VERSION 5.7 ;
BUSBITCHARS "[]" ;
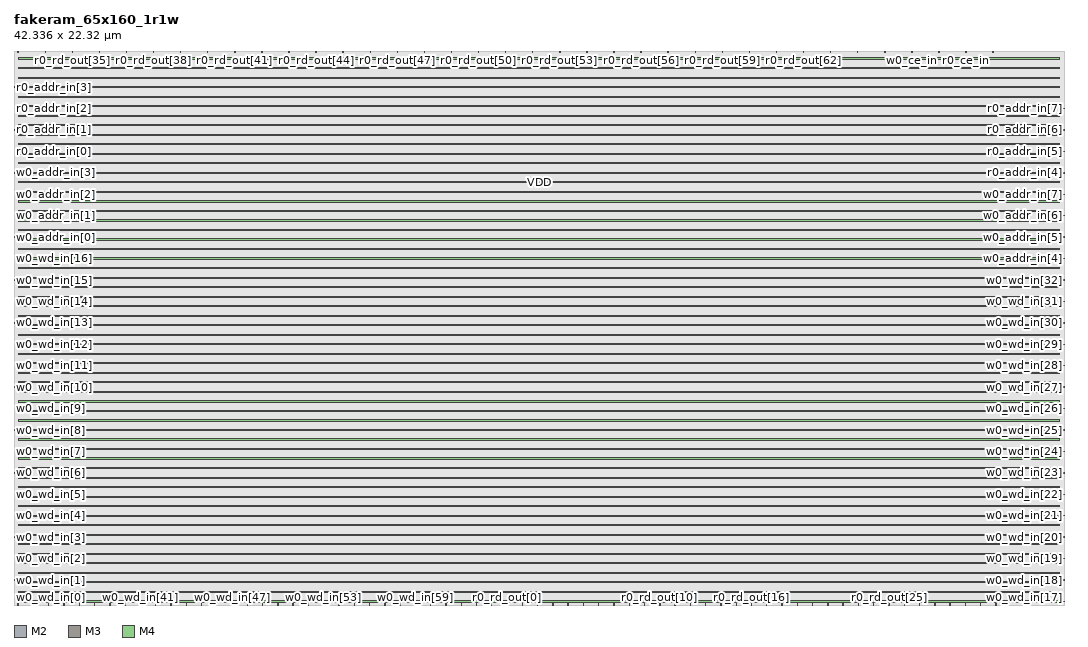
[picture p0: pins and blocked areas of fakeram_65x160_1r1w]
MACRO fakeram_65x160_1r1w
  FOREIGN fakeram_65x160_1r1w 0 0 ;
  SYMMETRY X Y R90 ;
  SIZE 42.336 BY 22.320 ;
  CLASS BLOCK ;
  PIN w0_wd_in[0]
    DIRECTION INPUT ;
    USE SIGNAL ;
    SHAPE ABUTMENT ;
    PORT
      LAYER M2 ;
      RECT 0.000 0.138 0.036 0.150 ;
    END
  END w0_wd_in[0]
  PIN w0_wd_in[1]
    DIRECTION INPUT ;
    USE SIGNAL ;
    SHAPE ABUTMENT ;
    PORT
      LAYER M2 ;
      RECT 0.000 1.002 0.036 1.014 ;
    END
  END w0_wd_in[1]
  PIN w0_wd_in[2]
    DIRECTION INPUT ;
    USE SIGNAL ;
    SHAPE ABUTMENT ;
    PORT
      LAYER M2 ;
      RECT 0.000 1.866 0.036 1.878 ;
    END
  END w0_wd_in[2]
  PIN w0_wd_in[3]
    DIRECTION INPUT ;
    USE SIGNAL ;
    SHAPE ABUTMENT ;
    PORT
      LAYER M2 ;
      RECT 0.000 2.730 0.036 2.742 ;
    END
  END w0_wd_in[3]
  PIN w0_wd_in[4]
    DIRECTION INPUT ;
    USE SIGNAL ;
    SHAPE ABUTMENT ;
    PORT
      LAYER M2 ;
      RECT 0.000 3.594 0.036 3.606 ;
    END
  END w0_wd_in[4]
  PIN w0_wd_in[5]
    DIRECTION INPUT ;
    USE SIGNAL ;
    SHAPE ABUTMENT ;
    PORT
      LAYER M2 ;
      RECT 0.000 4.458 0.036 4.470 ;
    END
  END w0_wd_in[5]
  PIN w0_wd_in[6]
    DIRECTION INPUT ;
    USE SIGNAL ;
    SHAPE ABUTMENT ;
    PORT
      LAYER M2 ;
      RECT 0.000 5.322 0.036 5.334 ;
    END
  END w0_wd_in[6]
  PIN w0_wd_in[7]
    DIRECTION INPUT ;
    USE SIGNAL ;
    SHAPE ABUTMENT ;
    PORT
      LAYER M2 ;
      RECT 0.000 6.186 0.036 6.198 ;
    END
  END w0_wd_in[7]
  PIN w0_wd_in[8]
    DIRECTION INPUT ;
    USE SIGNAL ;
    SHAPE ABUTMENT ;
    PORT
      LAYER M2 ;
      RECT 0.000 7.050 0.036 7.062 ;
    END
  END w0_wd_in[8]
  PIN w0_wd_in[9]
    DIRECTION INPUT ;
    USE SIGNAL ;
    SHAPE ABUTMENT ;
    PORT
      LAYER M2 ;
      RECT 0.000 7.914 0.036 7.926 ;
    END
  END w0_wd_in[9]
  PIN w0_wd_in[10]
    DIRECTION INPUT ;
    USE SIGNAL ;
    SHAPE ABUTMENT ;
    PORT
      LAYER M2 ;
      RECT 0.000 8.778 0.036 8.790 ;
    END
  END w0_wd_in[10]
  PIN w0_wd_in[11]
    DIRECTION INPUT ;
    USE SIGNAL ;
    SHAPE ABUTMENT ;
    PORT
      LAYER M2 ;
      RECT 0.000 9.642 0.036 9.654 ;
    END
  END w0_wd_in[11]
  PIN w0_wd_in[12]
    DIRECTION INPUT ;
    USE SIGNAL ;
    SHAPE ABUTMENT ;
    PORT
      LAYER M2 ;
      RECT 0.000 10.506 0.036 10.518 ;
    END
  END w0_wd_in[12]
  PIN w0_wd_in[13]
    DIRECTION INPUT ;
    USE SIGNAL ;
    SHAPE ABUTMENT ;
    PORT
      LAYER M2 ;
      RECT 0.000 11.370 0.036 11.382 ;
    END
  END w0_wd_in[13]
  PIN w0_wd_in[14]
    DIRECTION INPUT ;
    USE SIGNAL ;
    SHAPE ABUTMENT ;
    PORT
      LAYER M2 ;
      RECT 0.000 12.234 0.036 12.246 ;
    END
  END w0_wd_in[14]
  PIN w0_wd_in[15]
    DIRECTION INPUT ;
    USE SIGNAL ;
    SHAPE ABUTMENT ;
    PORT
      LAYER M2 ;
      RECT 0.000 13.098 0.036 13.110 ;
    END
  END w0_wd_in[15]
  PIN w0_wd_in[16]
    DIRECTION INPUT ;
    USE SIGNAL ;
    SHAPE ABUTMENT ;
    PORT
      LAYER M2 ;
      RECT 0.000 13.962 0.036 13.974 ;
    END
  END w0_wd_in[16]
  PIN w0_wd_in[17]
    DIRECTION INPUT ;
    USE SIGNAL ;
    SHAPE ABUTMENT ;
    PORT
      LAYER M2 ;
      RECT 42.300 0.138 42.336 0.150 ;
    END
  END w0_wd_in[17]
  PIN w0_wd_in[18]
    DIRECTION INPUT ;
    USE SIGNAL ;
    SHAPE ABUTMENT ;
    PORT
      LAYER M2 ;
      RECT 42.300 1.002 42.336 1.014 ;
    END
  END w0_wd_in[18]
  PIN w0_wd_in[19]
    DIRECTION INPUT ;
    USE SIGNAL ;
    SHAPE ABUTMENT ;
    PORT
      LAYER M2 ;
      RECT 42.300 1.866 42.336 1.878 ;
    END
  END w0_wd_in[19]
  PIN w0_wd_in[20]
    DIRECTION INPUT ;
    USE SIGNAL ;
    SHAPE ABUTMENT ;
    PORT
      LAYER M2 ;
      RECT 42.300 2.730 42.336 2.742 ;
    END
  END w0_wd_in[20]
  PIN w0_wd_in[21]
    DIRECTION INPUT ;
    USE SIGNAL ;
    SHAPE ABUTMENT ;
    PORT
      LAYER M2 ;
      RECT 42.300 3.594 42.336 3.606 ;
    END
  END w0_wd_in[21]
  PIN w0_wd_in[22]
    DIRECTION INPUT ;
    USE SIGNAL ;
    SHAPE ABUTMENT ;
    PORT
      LAYER M2 ;
      RECT 42.300 4.458 42.336 4.470 ;
    END
  END w0_wd_in[22]
  PIN w0_wd_in[23]
    DIRECTION INPUT ;
    USE SIGNAL ;
    SHAPE ABUTMENT ;
    PORT
      LAYER M2 ;
      RECT 42.300 5.322 42.336 5.334 ;
    END
  END w0_wd_in[23]
  PIN w0_wd_in[24]
    DIRECTION INPUT ;
    USE SIGNAL ;
    SHAPE ABUTMENT ;
    PORT
      LAYER M2 ;
      RECT 42.300 6.186 42.336 6.198 ;
    END
  END w0_wd_in[24]
  PIN w0_wd_in[25]
    DIRECTION INPUT ;
    USE SIGNAL ;
    SHAPE ABUTMENT ;
    PORT
      LAYER M2 ;
      RECT 42.300 7.050 42.336 7.062 ;
    END
  END w0_wd_in[25]
  PIN w0_wd_in[26]
    DIRECTION INPUT ;
    USE SIGNAL ;
    SHAPE ABUTMENT ;
    PORT
      LAYER M2 ;
      RECT 42.300 7.914 42.336 7.926 ;
    END
  END w0_wd_in[26]
  PIN w0_wd_in[27]
    DIRECTION INPUT ;
    USE SIGNAL ;
    SHAPE ABUTMENT ;
    PORT
      LAYER M2 ;
      RECT 42.300 8.778 42.336 8.790 ;
    END
  END w0_wd_in[27]
  PIN w0_wd_in[28]
    DIRECTION INPUT ;
    USE SIGNAL ;
    SHAPE ABUTMENT ;
    PORT
      LAYER M2 ;
      RECT 42.300 9.642 42.336 9.654 ;
    END
  END w0_wd_in[28]
  PIN w0_wd_in[29]
    DIRECTION INPUT ;
    USE SIGNAL ;
    SHAPE ABUTMENT ;
    PORT
      LAYER M2 ;
      RECT 42.300 10.506 42.336 10.518 ;
    END
  END w0_wd_in[29]
  PIN w0_wd_in[30]
    DIRECTION INPUT ;
    USE SIGNAL ;
    SHAPE ABUTMENT ;
    PORT
      LAYER M2 ;
      RECT 42.300 11.370 42.336 11.382 ;
    END
  END w0_wd_in[30]
  PIN w0_wd_in[31]
    DIRECTION INPUT ;
    USE SIGNAL ;
    SHAPE ABUTMENT ;
    PORT
      LAYER M2 ;
      RECT 42.300 12.234 42.336 12.246 ;
    END
  END w0_wd_in[31]
  PIN w0_wd_in[32]
    DIRECTION INPUT ;
    USE SIGNAL ;
    SHAPE ABUTMENT ;
    PORT
      LAYER M2 ;
      RECT 42.300 13.098 42.336 13.110 ;
    END
  END w0_wd_in[32]
  PIN w0_wd_in[33]
    DIRECTION INPUT ;
    USE SIGNAL ;
    SHAPE ABUTMENT ;
    PORT
      LAYER M3 ;
      RECT 0.161 0.000 0.175 0.042 ;
    END
  END w0_wd_in[33]
  PIN w0_wd_in[34]
    DIRECTION INPUT ;
    USE SIGNAL ;
    SHAPE ABUTMENT ;
    PORT
      LAYER M3 ;
      RECT 0.777 0.000 0.791 0.042 ;
    END
  END w0_wd_in[34]
  PIN w0_wd_in[35]
    DIRECTION INPUT ;
    USE SIGNAL ;
    SHAPE ABUTMENT ;
    PORT
      LAYER M3 ;
      RECT 1.393 0.000 1.407 0.042 ;
    END
  END w0_wd_in[35]
  PIN w0_wd_in[36]
    DIRECTION INPUT ;
    USE SIGNAL ;
    SHAPE ABUTMENT ;
    PORT
      LAYER M3 ;
      RECT 2.009 0.000 2.023 0.042 ;
    END
  END w0_wd_in[36]
  PIN w0_wd_in[37]
    DIRECTION INPUT ;
    USE SIGNAL ;
    SHAPE ABUTMENT ;
    PORT
      LAYER M3 ;
      RECT 2.625 0.000 2.639 0.042 ;
    END
  END w0_wd_in[37]
  PIN w0_wd_in[38]
    DIRECTION INPUT ;
    USE SIGNAL ;
    SHAPE ABUTMENT ;
    PORT
      LAYER M3 ;
      RECT 3.241 0.000 3.255 0.042 ;
    END
  END w0_wd_in[38]
  PIN w0_wd_in[39]
    DIRECTION INPUT ;
    USE SIGNAL ;
    SHAPE ABUTMENT ;
    PORT
      LAYER M3 ;
      RECT 3.857 0.000 3.871 0.042 ;
    END
  END w0_wd_in[39]
  PIN w0_wd_in[40]
    DIRECTION INPUT ;
    USE SIGNAL ;
    SHAPE ABUTMENT ;
    PORT
      LAYER M3 ;
      RECT 4.473 0.000 4.487 0.042 ;
    END
  END w0_wd_in[40]
  PIN w0_wd_in[41]
    DIRECTION INPUT ;
    USE SIGNAL ;
    SHAPE ABUTMENT ;
    PORT
      LAYER M3 ;
      RECT 5.089 0.000 5.103 0.042 ;
    END
  END w0_wd_in[41]
  PIN w0_wd_in[42]
    DIRECTION INPUT ;
    USE SIGNAL ;
    SHAPE ABUTMENT ;
    PORT
      LAYER M3 ;
      RECT 5.705 0.000 5.719 0.042 ;
    END
  END w0_wd_in[42]
  PIN w0_wd_in[43]
    DIRECTION INPUT ;
    USE SIGNAL ;
    SHAPE ABUTMENT ;
    PORT
      LAYER M3 ;
      RECT 6.321 0.000 6.335 0.042 ;
    END
  END w0_wd_in[43]
  PIN w0_wd_in[44]
    DIRECTION INPUT ;
    USE SIGNAL ;
    SHAPE ABUTMENT ;
    PORT
      LAYER M3 ;
      RECT 6.937 0.000 6.951 0.042 ;
    END
  END w0_wd_in[44]
  PIN w0_wd_in[45]
    DIRECTION INPUT ;
    USE SIGNAL ;
    SHAPE ABUTMENT ;
    PORT
      LAYER M3 ;
      RECT 7.553 0.000 7.567 0.042 ;
    END
  END w0_wd_in[45]
  PIN w0_wd_in[46]
    DIRECTION INPUT ;
    USE SIGNAL ;
    SHAPE ABUTMENT ;
    PORT
      LAYER M3 ;
      RECT 8.169 0.000 8.183 0.042 ;
    END
  END w0_wd_in[46]
  PIN w0_wd_in[47]
    DIRECTION INPUT ;
    USE SIGNAL ;
    SHAPE ABUTMENT ;
    PORT
      LAYER M3 ;
      RECT 8.785 0.000 8.799 0.042 ;
    END
  END w0_wd_in[47]
  PIN w0_wd_in[48]
    DIRECTION INPUT ;
    USE SIGNAL ;
    SHAPE ABUTMENT ;
    PORT
      LAYER M3 ;
      RECT 9.401 0.000 9.415 0.042 ;
    END
  END w0_wd_in[48]
  PIN w0_wd_in[49]
    DIRECTION INPUT ;
    USE SIGNAL ;
    SHAPE ABUTMENT ;
    PORT
      LAYER M3 ;
      RECT 10.017 0.000 10.031 0.042 ;
    END
  END w0_wd_in[49]
  PIN w0_wd_in[50]
    DIRECTION INPUT ;
    USE SIGNAL ;
    SHAPE ABUTMENT ;
    PORT
      LAYER M3 ;
      RECT 10.633 0.000 10.647 0.042 ;
    END
  END w0_wd_in[50]
  PIN w0_wd_in[51]
    DIRECTION INPUT ;
    USE SIGNAL ;
    SHAPE ABUTMENT ;
    PORT
      LAYER M3 ;
      RECT 11.249 0.000 11.263 0.042 ;
    END
  END w0_wd_in[51]
  PIN w0_wd_in[52]
    DIRECTION INPUT ;
    USE SIGNAL ;
    SHAPE ABUTMENT ;
    PORT
      LAYER M3 ;
      RECT 11.865 0.000 11.879 0.042 ;
    END
  END w0_wd_in[52]
  PIN w0_wd_in[53]
    DIRECTION INPUT ;
    USE SIGNAL ;
    SHAPE ABUTMENT ;
    PORT
      LAYER M3 ;
      RECT 12.481 0.000 12.495 0.042 ;
    END
  END w0_wd_in[53]
  PIN w0_wd_in[54]
    DIRECTION INPUT ;
    USE SIGNAL ;
    SHAPE ABUTMENT ;
    PORT
      LAYER M3 ;
      RECT 13.097 0.000 13.111 0.042 ;
    END
  END w0_wd_in[54]
  PIN w0_wd_in[55]
    DIRECTION INPUT ;
    USE SIGNAL ;
    SHAPE ABUTMENT ;
    PORT
      LAYER M3 ;
      RECT 13.713 0.000 13.727 0.042 ;
    END
  END w0_wd_in[55]
  PIN w0_wd_in[56]
    DIRECTION INPUT ;
    USE SIGNAL ;
    SHAPE ABUTMENT ;
    PORT
      LAYER M3 ;
      RECT 14.329 0.000 14.343 0.042 ;
    END
  END w0_wd_in[56]
  PIN w0_wd_in[57]
    DIRECTION INPUT ;
    USE SIGNAL ;
    SHAPE ABUTMENT ;
    PORT
      LAYER M3 ;
      RECT 14.945 0.000 14.959 0.042 ;
    END
  END w0_wd_in[57]
  PIN w0_wd_in[58]
    DIRECTION INPUT ;
    USE SIGNAL ;
    SHAPE ABUTMENT ;
    PORT
      LAYER M3 ;
      RECT 15.561 0.000 15.575 0.042 ;
    END
  END w0_wd_in[58]
  PIN w0_wd_in[59]
    DIRECTION INPUT ;
    USE SIGNAL ;
    SHAPE ABUTMENT ;
    PORT
      LAYER M3 ;
      RECT 16.177 0.000 16.191 0.042 ;
    END
  END w0_wd_in[59]
  PIN w0_wd_in[60]
    DIRECTION INPUT ;
    USE SIGNAL ;
    SHAPE ABUTMENT ;
    PORT
      LAYER M3 ;
      RECT 16.793 0.000 16.807 0.042 ;
    END
  END w0_wd_in[60]
  PIN w0_wd_in[61]
    DIRECTION INPUT ;
    USE SIGNAL ;
    SHAPE ABUTMENT ;
    PORT
      LAYER M3 ;
      RECT 17.409 0.000 17.423 0.042 ;
    END
  END w0_wd_in[61]
  PIN w0_wd_in[62]
    DIRECTION INPUT ;
    USE SIGNAL ;
    SHAPE ABUTMENT ;
    PORT
      LAYER M3 ;
      RECT 18.025 0.000 18.039 0.042 ;
    END
  END w0_wd_in[62]
  PIN w0_wd_in[63]
    DIRECTION INPUT ;
    USE SIGNAL ;
    SHAPE ABUTMENT ;
    PORT
      LAYER M3 ;
      RECT 18.641 0.000 18.655 0.042 ;
    END
  END w0_wd_in[63]
  PIN w0_wd_in[64]
    DIRECTION INPUT ;
    USE SIGNAL ;
    SHAPE ABUTMENT ;
    PORT
      LAYER M3 ;
      RECT 19.257 0.000 19.271 0.042 ;
    END
  END w0_wd_in[64]
  PIN r0_rd_out[0]
    DIRECTION OUTPUT ;
    USE SIGNAL ;
    SHAPE ABUTMENT ;
    PORT
      LAYER M3 ;
      RECT 19.873 0.000 19.887 0.042 ;
    END
  END r0_rd_out[0]
  PIN r0_rd_out[1]
    DIRECTION OUTPUT ;
    USE SIGNAL ;
    SHAPE ABUTMENT ;
    PORT
      LAYER M3 ;
      RECT 20.489 0.000 20.503 0.042 ;
    END
  END r0_rd_out[1]
  PIN r0_rd_out[2]
    DIRECTION OUTPUT ;
    USE SIGNAL ;
    SHAPE ABUTMENT ;
    PORT
      LAYER M3 ;
      RECT 21.105 0.000 21.119 0.042 ;
    END
  END r0_rd_out[2]
  PIN r0_rd_out[3]
    DIRECTION OUTPUT ;
    USE SIGNAL ;
    SHAPE ABUTMENT ;
    PORT
      LAYER M3 ;
      RECT 21.721 0.000 21.735 0.042 ;
    END
  END r0_rd_out[3]
  PIN r0_rd_out[4]
    DIRECTION OUTPUT ;
    USE SIGNAL ;
    SHAPE ABUTMENT ;
    PORT
      LAYER M3 ;
      RECT 22.337 0.000 22.351 0.042 ;
    END
  END r0_rd_out[4]
  PIN r0_rd_out[5]
    DIRECTION OUTPUT ;
    USE SIGNAL ;
    SHAPE ABUTMENT ;
    PORT
      LAYER M3 ;
      RECT 22.953 0.000 22.967 0.042 ;
    END
  END r0_rd_out[5]
  PIN r0_rd_out[6]
    DIRECTION OUTPUT ;
    USE SIGNAL ;
    SHAPE ABUTMENT ;
    PORT
      LAYER M3 ;
      RECT 23.569 0.000 23.583 0.042 ;
    END
  END r0_rd_out[6]
  PIN r0_rd_out[7]
    DIRECTION OUTPUT ;
    USE SIGNAL ;
    SHAPE ABUTMENT ;
    PORT
      LAYER M3 ;
      RECT 24.185 0.000 24.199 0.042 ;
    END
  END r0_rd_out[7]
  PIN r0_rd_out[8]
    DIRECTION OUTPUT ;
    USE SIGNAL ;
    SHAPE ABUTMENT ;
    PORT
      LAYER M3 ;
      RECT 24.801 0.000 24.815 0.042 ;
    END
  END r0_rd_out[8]
  PIN r0_rd_out[9]
    DIRECTION OUTPUT ;
    USE SIGNAL ;
    SHAPE ABUTMENT ;
    PORT
      LAYER M3 ;
      RECT 25.417 0.000 25.431 0.042 ;
    END
  END r0_rd_out[9]
  PIN r0_rd_out[10]
    DIRECTION OUTPUT ;
    USE SIGNAL ;
    SHAPE ABUTMENT ;
    PORT
      LAYER M3 ;
      RECT 26.033 0.000 26.047 0.042 ;
    END
  END r0_rd_out[10]
  PIN r0_rd_out[11]
    DIRECTION OUTPUT ;
    USE SIGNAL ;
    SHAPE ABUTMENT ;
    PORT
      LAYER M3 ;
      RECT 26.649 0.000 26.663 0.042 ;
    END
  END r0_rd_out[11]
  PIN r0_rd_out[12]
    DIRECTION OUTPUT ;
    USE SIGNAL ;
    SHAPE ABUTMENT ;
    PORT
      LAYER M3 ;
      RECT 27.265 0.000 27.279 0.042 ;
    END
  END r0_rd_out[12]
  PIN r0_rd_out[13]
    DIRECTION OUTPUT ;
    USE SIGNAL ;
    SHAPE ABUTMENT ;
    PORT
      LAYER M3 ;
      RECT 27.881 0.000 27.895 0.042 ;
    END
  END r0_rd_out[13]
  PIN r0_rd_out[14]
    DIRECTION OUTPUT ;
    USE SIGNAL ;
    SHAPE ABUTMENT ;
    PORT
      LAYER M3 ;
      RECT 28.497 0.000 28.511 0.042 ;
    END
  END r0_rd_out[14]
  PIN r0_rd_out[15]
    DIRECTION OUTPUT ;
    USE SIGNAL ;
    SHAPE ABUTMENT ;
    PORT
      LAYER M3 ;
      RECT 29.113 0.000 29.127 0.042 ;
    END
  END r0_rd_out[15]
  PIN r0_rd_out[16]
    DIRECTION OUTPUT ;
    USE SIGNAL ;
    SHAPE ABUTMENT ;
    PORT
      LAYER M3 ;
      RECT 29.729 0.000 29.743 0.042 ;
    END
  END r0_rd_out[16]
  PIN r0_rd_out[17]
    DIRECTION OUTPUT ;
    USE SIGNAL ;
    SHAPE ABUTMENT ;
    PORT
      LAYER M3 ;
      RECT 30.345 0.000 30.359 0.042 ;
    END
  END r0_rd_out[17]
  PIN r0_rd_out[18]
    DIRECTION OUTPUT ;
    USE SIGNAL ;
    SHAPE ABUTMENT ;
    PORT
      LAYER M3 ;
      RECT 30.961 0.000 30.975 0.042 ;
    END
  END r0_rd_out[18]
  PIN r0_rd_out[19]
    DIRECTION OUTPUT ;
    USE SIGNAL ;
    SHAPE ABUTMENT ;
    PORT
      LAYER M3 ;
      RECT 31.577 0.000 31.591 0.042 ;
    END
  END r0_rd_out[19]
  PIN r0_rd_out[20]
    DIRECTION OUTPUT ;
    USE SIGNAL ;
    SHAPE ABUTMENT ;
    PORT
      LAYER M3 ;
      RECT 32.193 0.000 32.207 0.042 ;
    END
  END r0_rd_out[20]
  PIN r0_rd_out[21]
    DIRECTION OUTPUT ;
    USE SIGNAL ;
    SHAPE ABUTMENT ;
    PORT
      LAYER M3 ;
      RECT 32.809 0.000 32.823 0.042 ;
    END
  END r0_rd_out[21]
  PIN r0_rd_out[22]
    DIRECTION OUTPUT ;
    USE SIGNAL ;
    SHAPE ABUTMENT ;
    PORT
      LAYER M3 ;
      RECT 33.425 0.000 33.439 0.042 ;
    END
  END r0_rd_out[22]
  PIN r0_rd_out[23]
    DIRECTION OUTPUT ;
    USE SIGNAL ;
    SHAPE ABUTMENT ;
    PORT
      LAYER M3 ;
      RECT 34.041 0.000 34.055 0.042 ;
    END
  END r0_rd_out[23]
  PIN r0_rd_out[24]
    DIRECTION OUTPUT ;
    USE SIGNAL ;
    SHAPE ABUTMENT ;
    PORT
      LAYER M3 ;
      RECT 34.657 0.000 34.671 0.042 ;
    END
  END r0_rd_out[24]
  PIN r0_rd_out[25]
    DIRECTION OUTPUT ;
    USE SIGNAL ;
    SHAPE ABUTMENT ;
    PORT
      LAYER M3 ;
      RECT 35.273 0.000 35.287 0.042 ;
    END
  END r0_rd_out[25]
  PIN r0_rd_out[26]
    DIRECTION OUTPUT ;
    USE SIGNAL ;
    SHAPE ABUTMENT ;
    PORT
      LAYER M3 ;
      RECT 35.889 0.000 35.903 0.042 ;
    END
  END r0_rd_out[26]
  PIN r0_rd_out[27]
    DIRECTION OUTPUT ;
    USE SIGNAL ;
    SHAPE ABUTMENT ;
    PORT
      LAYER M3 ;
      RECT 36.505 0.000 36.519 0.042 ;
    END
  END r0_rd_out[27]
  PIN r0_rd_out[28]
    DIRECTION OUTPUT ;
    USE SIGNAL ;
    SHAPE ABUTMENT ;
    PORT
      LAYER M3 ;
      RECT 37.121 0.000 37.135 0.042 ;
    END
  END r0_rd_out[28]
  PIN r0_rd_out[29]
    DIRECTION OUTPUT ;
    USE SIGNAL ;
    SHAPE ABUTMENT ;
    PORT
      LAYER M3 ;
      RECT 37.737 0.000 37.751 0.042 ;
    END
  END r0_rd_out[29]
  PIN r0_rd_out[30]
    DIRECTION OUTPUT ;
    USE SIGNAL ;
    SHAPE ABUTMENT ;
    PORT
      LAYER M3 ;
      RECT 38.353 0.000 38.367 0.042 ;
    END
  END r0_rd_out[30]
  PIN r0_rd_out[31]
    DIRECTION OUTPUT ;
    USE SIGNAL ;
    SHAPE ABUTMENT ;
    PORT
      LAYER M3 ;
      RECT 38.969 0.000 38.983 0.042 ;
    END
  END r0_rd_out[31]
  PIN r0_rd_out[32]
    DIRECTION OUTPUT ;
    USE SIGNAL ;
    SHAPE ABUTMENT ;
    PORT
      LAYER M3 ;
      RECT 39.585 0.000 39.599 0.042 ;
    END
  END r0_rd_out[32]
  PIN r0_rd_out[33]
    DIRECTION OUTPUT ;
    USE SIGNAL ;
    SHAPE ABUTMENT ;
    PORT
      LAYER M3 ;
      RECT 0.161 22.278 0.175 22.320 ;
    END
  END r0_rd_out[33]
  PIN r0_rd_out[34]
    DIRECTION OUTPUT ;
    USE SIGNAL ;
    SHAPE ABUTMENT ;
    PORT
      LAYER M3 ;
      RECT 1.253 22.278 1.267 22.320 ;
    END
  END r0_rd_out[34]
  PIN r0_rd_out[35]
    DIRECTION OUTPUT ;
    USE SIGNAL ;
    SHAPE ABUTMENT ;
    PORT
      LAYER M3 ;
      RECT 2.345 22.278 2.359 22.320 ;
    END
  END r0_rd_out[35]
  PIN r0_rd_out[36]
    DIRECTION OUTPUT ;
    USE SIGNAL ;
    SHAPE ABUTMENT ;
    PORT
      LAYER M3 ;
      RECT 3.437 22.278 3.451 22.320 ;
    END
  END r0_rd_out[36]
  PIN r0_rd_out[37]
    DIRECTION OUTPUT ;
    USE SIGNAL ;
    SHAPE ABUTMENT ;
    PORT
      LAYER M3 ;
      RECT 4.529 22.278 4.543 22.320 ;
    END
  END r0_rd_out[37]
  PIN r0_rd_out[38]
    DIRECTION OUTPUT ;
    USE SIGNAL ;
    SHAPE ABUTMENT ;
    PORT
      LAYER M3 ;
      RECT 5.621 22.278 5.635 22.320 ;
    END
  END r0_rd_out[38]
  PIN r0_rd_out[39]
    DIRECTION OUTPUT ;
    USE SIGNAL ;
    SHAPE ABUTMENT ;
    PORT
      LAYER M3 ;
      RECT 6.713 22.278 6.727 22.320 ;
    END
  END r0_rd_out[39]
  PIN r0_rd_out[40]
    DIRECTION OUTPUT ;
    USE SIGNAL ;
    SHAPE ABUTMENT ;
    PORT
      LAYER M3 ;
      RECT 7.805 22.278 7.819 22.320 ;
    END
  END r0_rd_out[40]
  PIN r0_rd_out[41]
    DIRECTION OUTPUT ;
    USE SIGNAL ;
    SHAPE ABUTMENT ;
    PORT
      LAYER M3 ;
      RECT 8.897 22.278 8.911 22.320 ;
    END
  END r0_rd_out[41]
  PIN r0_rd_out[42]
    DIRECTION OUTPUT ;
    USE SIGNAL ;
    SHAPE ABUTMENT ;
    PORT
      LAYER M3 ;
      RECT 9.989 22.278 10.003 22.320 ;
    END
  END r0_rd_out[42]
  PIN r0_rd_out[43]
    DIRECTION OUTPUT ;
    USE SIGNAL ;
    SHAPE ABUTMENT ;
    PORT
      LAYER M3 ;
      RECT 11.081 22.278 11.095 22.320 ;
    END
  END r0_rd_out[43]
  PIN r0_rd_out[44]
    DIRECTION OUTPUT ;
    USE SIGNAL ;
    SHAPE ABUTMENT ;
    PORT
      LAYER M3 ;
      RECT 12.173 22.278 12.187 22.320 ;
    END
  END r0_rd_out[44]
  PIN r0_rd_out[45]
    DIRECTION OUTPUT ;
    USE SIGNAL ;
    SHAPE ABUTMENT ;
    PORT
      LAYER M3 ;
      RECT 13.265 22.278 13.279 22.320 ;
    END
  END r0_rd_out[45]
  PIN r0_rd_out[46]
    DIRECTION OUTPUT ;
    USE SIGNAL ;
    SHAPE ABUTMENT ;
    PORT
      LAYER M3 ;
      RECT 14.357 22.278 14.371 22.320 ;
    END
  END r0_rd_out[46]
  PIN r0_rd_out[47]
    DIRECTION OUTPUT ;
    USE SIGNAL ;
    SHAPE ABUTMENT ;
    PORT
      LAYER M3 ;
      RECT 15.449 22.278 15.463 22.320 ;
    END
  END r0_rd_out[47]
  PIN r0_rd_out[48]
    DIRECTION OUTPUT ;
    USE SIGNAL ;
    SHAPE ABUTMENT ;
    PORT
      LAYER M3 ;
      RECT 16.541 22.278 16.555 22.320 ;
    END
  END r0_rd_out[48]
  PIN r0_rd_out[49]
    DIRECTION OUTPUT ;
    USE SIGNAL ;
    SHAPE ABUTMENT ;
    PORT
      LAYER M3 ;
      RECT 17.633 22.278 17.647 22.320 ;
    END
  END r0_rd_out[49]
  PIN r0_rd_out[50]
    DIRECTION OUTPUT ;
    USE SIGNAL ;
    SHAPE ABUTMENT ;
    PORT
      LAYER M3 ;
      RECT 18.725 22.278 18.739 22.320 ;
    END
  END r0_rd_out[50]
  PIN r0_rd_out[51]
    DIRECTION OUTPUT ;
    USE SIGNAL ;
    SHAPE ABUTMENT ;
    PORT
      LAYER M3 ;
      RECT 19.817 22.278 19.831 22.320 ;
    END
  END r0_rd_out[51]
  PIN r0_rd_out[52]
    DIRECTION OUTPUT ;
    USE SIGNAL ;
    SHAPE ABUTMENT ;
    PORT
      LAYER M3 ;
      RECT 20.909 22.278 20.923 22.320 ;
    END
  END r0_rd_out[52]
  PIN r0_rd_out[53]
    DIRECTION OUTPUT ;
    USE SIGNAL ;
    SHAPE ABUTMENT ;
    PORT
      LAYER M3 ;
      RECT 22.001 22.278 22.015 22.320 ;
    END
  END r0_rd_out[53]
  PIN r0_rd_out[54]
    DIRECTION OUTPUT ;
    USE SIGNAL ;
    SHAPE ABUTMENT ;
    PORT
      LAYER M3 ;
      RECT 23.093 22.278 23.107 22.320 ;
    END
  END r0_rd_out[54]
  PIN r0_rd_out[55]
    DIRECTION OUTPUT ;
    USE SIGNAL ;
    SHAPE ABUTMENT ;
    PORT
      LAYER M3 ;
      RECT 24.185 22.278 24.199 22.320 ;
    END
  END r0_rd_out[55]
  PIN r0_rd_out[56]
    DIRECTION OUTPUT ;
    USE SIGNAL ;
    SHAPE ABUTMENT ;
    PORT
      LAYER M3 ;
      RECT 25.277 22.278 25.291 22.320 ;
    END
  END r0_rd_out[56]
  PIN r0_rd_out[57]
    DIRECTION OUTPUT ;
    USE SIGNAL ;
    SHAPE ABUTMENT ;
    PORT
      LAYER M3 ;
      RECT 26.369 22.278 26.383 22.320 ;
    END
  END r0_rd_out[57]
  PIN r0_rd_out[58]
    DIRECTION OUTPUT ;
    USE SIGNAL ;
    SHAPE ABUTMENT ;
    PORT
      LAYER M3 ;
      RECT 27.461 22.278 27.475 22.320 ;
    END
  END r0_rd_out[58]
  PIN r0_rd_out[59]
    DIRECTION OUTPUT ;
    USE SIGNAL ;
    SHAPE ABUTMENT ;
    PORT
      LAYER M3 ;
      RECT 28.553 22.278 28.567 22.320 ;
    END
  END r0_rd_out[59]
  PIN r0_rd_out[60]
    DIRECTION OUTPUT ;
    USE SIGNAL ;
    SHAPE ABUTMENT ;
    PORT
      LAYER M3 ;
      RECT 29.645 22.278 29.659 22.320 ;
    END
  END r0_rd_out[60]
  PIN r0_rd_out[61]
    DIRECTION OUTPUT ;
    USE SIGNAL ;
    SHAPE ABUTMENT ;
    PORT
      LAYER M3 ;
      RECT 30.737 22.278 30.751 22.320 ;
    END
  END r0_rd_out[61]
  PIN r0_rd_out[62]
    DIRECTION OUTPUT ;
    USE SIGNAL ;
    SHAPE ABUTMENT ;
    PORT
      LAYER M3 ;
      RECT 31.829 22.278 31.843 22.320 ;
    END
  END r0_rd_out[62]
  PIN r0_rd_out[63]
    DIRECTION OUTPUT ;
    USE SIGNAL ;
    SHAPE ABUTMENT ;
    PORT
      LAYER M3 ;
      RECT 32.921 22.278 32.935 22.320 ;
    END
  END r0_rd_out[63]
  PIN r0_rd_out[64]
    DIRECTION OUTPUT ;
    USE SIGNAL ;
    SHAPE ABUTMENT ;
    PORT
      LAYER M3 ;
      RECT 34.013 22.278 34.027 22.320 ;
    END
  END r0_rd_out[64]
  PIN w0_addr_in[0]
    DIRECTION INPUT ;
    USE SIGNAL ;
    SHAPE ABUTMENT ;
    PORT
      LAYER M2 ;
      RECT 0.000 14.826 0.036 14.838 ;
    END
  END w0_addr_in[0]
  PIN w0_addr_in[1]
    DIRECTION INPUT ;
    USE SIGNAL ;
    SHAPE ABUTMENT ;
    PORT
      LAYER M2 ;
      RECT 0.000 15.690 0.036 15.702 ;
    END
  END w0_addr_in[1]
  PIN w0_addr_in[2]
    DIRECTION INPUT ;
    USE SIGNAL ;
    SHAPE ABUTMENT ;
    PORT
      LAYER M2 ;
      RECT 0.000 16.554 0.036 16.566 ;
    END
  END w0_addr_in[2]
  PIN w0_addr_in[3]
    DIRECTION INPUT ;
    USE SIGNAL ;
    SHAPE ABUTMENT ;
    PORT
      LAYER M2 ;
      RECT 0.000 17.418 0.036 17.430 ;
    END
  END w0_addr_in[3]
  PIN w0_addr_in[4]
    DIRECTION INPUT ;
    USE SIGNAL ;
    SHAPE ABUTMENT ;
    PORT
      LAYER M2 ;
      RECT 42.300 13.962 42.336 13.974 ;
    END
  END w0_addr_in[4]
  PIN w0_addr_in[5]
    DIRECTION INPUT ;
    USE SIGNAL ;
    SHAPE ABUTMENT ;
    PORT
      LAYER M2 ;
      RECT 42.300 14.826 42.336 14.838 ;
    END
  END w0_addr_in[5]
  PIN w0_addr_in[6]
    DIRECTION INPUT ;
    USE SIGNAL ;
    SHAPE ABUTMENT ;
    PORT
      LAYER M2 ;
      RECT 42.300 15.690 42.336 15.702 ;
    END
  END w0_addr_in[6]
  PIN w0_addr_in[7]
    DIRECTION INPUT ;
    USE SIGNAL ;
    SHAPE ABUTMENT ;
    PORT
      LAYER M2 ;
      RECT 42.300 16.554 42.336 16.566 ;
    END
  END w0_addr_in[7]
  PIN r0_addr_in[0]
    DIRECTION INPUT ;
    USE SIGNAL ;
    SHAPE ABUTMENT ;
    PORT
      LAYER M2 ;
      RECT 0.000 18.282 0.036 18.294 ;
    END
  END r0_addr_in[0]
  PIN r0_addr_in[1]
    DIRECTION INPUT ;
    USE SIGNAL ;
    SHAPE ABUTMENT ;
    PORT
      LAYER M2 ;
      RECT 0.000 19.146 0.036 19.158 ;
    END
  END r0_addr_in[1]
  PIN r0_addr_in[2]
    DIRECTION INPUT ;
    USE SIGNAL ;
    SHAPE ABUTMENT ;
    PORT
      LAYER M2 ;
      RECT 0.000 20.010 0.036 20.022 ;
    END
  END r0_addr_in[2]
  PIN r0_addr_in[3]
    DIRECTION INPUT ;
    USE SIGNAL ;
    SHAPE ABUTMENT ;
    PORT
      LAYER M2 ;
      RECT 0.000 20.874 0.036 20.886 ;
    END
  END r0_addr_in[3]
  PIN r0_addr_in[4]
    DIRECTION INPUT ;
    USE SIGNAL ;
    SHAPE ABUTMENT ;
    PORT
      LAYER M2 ;
      RECT 42.300 17.418 42.336 17.430 ;
    END
  END r0_addr_in[4]
  PIN r0_addr_in[5]
    DIRECTION INPUT ;
    USE SIGNAL ;
    SHAPE ABUTMENT ;
    PORT
      LAYER M2 ;
      RECT 42.300 18.282 42.336 18.294 ;
    END
  END r0_addr_in[5]
  PIN r0_addr_in[6]
    DIRECTION INPUT ;
    USE SIGNAL ;
    SHAPE ABUTMENT ;
    PORT
      LAYER M2 ;
      RECT 42.300 19.146 42.336 19.158 ;
    END
  END r0_addr_in[6]
  PIN r0_addr_in[7]
    DIRECTION INPUT ;
    USE SIGNAL ;
    SHAPE ABUTMENT ;
    PORT
      LAYER M2 ;
      RECT 42.300 20.010 42.336 20.022 ;
    END
  END r0_addr_in[7]
  PIN w0_we_in
    DIRECTION INPUT ;
    USE SIGNAL ;
    SHAPE ABUTMENT ;
    PORT
      LAYER M3 ;
      RECT 35.105 22.278 35.119 22.320 ;
    END
  END w0_we_in
  PIN w0_ce_in
    DIRECTION INPUT ;
    USE SIGNAL ;
    SHAPE ABUTMENT ;
    PORT
      LAYER M3 ;
      RECT 36.197 22.278 36.211 22.320 ;
    END
  END w0_ce_in
  PIN w0_clk
    DIRECTION INPUT ;
    USE SIGNAL ;
    SHAPE ABUTMENT ;
    PORT
      LAYER M3 ;
      RECT 37.289 22.278 37.303 22.320 ;
    END
  END w0_clk
  PIN r0_ce_in
    DIRECTION INPUT ;
    USE SIGNAL ;
    SHAPE ABUTMENT ;
    PORT
      LAYER M3 ;
      RECT 38.381 22.278 38.395 22.320 ;
    END
  END r0_ce_in
  PIN r0_clk
    DIRECTION INPUT ;
    USE SIGNAL ;
    SHAPE ABUTMENT ;
    PORT
      LAYER M3 ;
      RECT 39.473 22.278 39.487 22.320 ;
    END
  END r0_clk
  PIN VSS
    DIRECTION INOUT ;
    USE GROUND ;
    PORT
      LAYER M4 ;
      RECT 0.168 0.120 42.168 0.168 ;
      RECT 0.168 0.504 42.168 0.552 ;
      RECT 0.168 0.888 42.168 0.936 ;
      RECT 0.168 1.272 42.168 1.320 ;
      RECT 0.168 1.656 42.168 1.704 ;
      RECT 0.168 2.040 42.168 2.088 ;
      RECT 0.168 2.424 42.168 2.472 ;
      RECT 0.168 2.808 42.168 2.856 ;
      RECT 0.168 3.192 42.168 3.240 ;
      RECT 0.168 3.576 42.168 3.624 ;
      RECT 0.168 3.960 42.168 4.008 ;
      RECT 0.168 4.344 42.168 4.392 ;
      RECT 0.168 4.728 42.168 4.776 ;
      RECT 0.168 5.112 42.168 5.160 ;
      RECT 0.168 5.496 42.168 5.544 ;
      RECT 0.168 5.880 42.168 5.928 ;
      RECT 0.168 6.264 42.168 6.312 ;
      RECT 0.168 6.648 42.168 6.696 ;
      RECT 0.168 7.032 42.168 7.080 ;
      RECT 0.168 7.416 42.168 7.464 ;
      RECT 0.168 7.800 42.168 7.848 ;
      RECT 0.168 8.184 42.168 8.232 ;
      RECT 0.168 8.568 42.168 8.616 ;
      RECT 0.168 8.952 42.168 9.000 ;
      RECT 0.168 9.336 42.168 9.384 ;
      RECT 0.168 9.720 42.168 9.768 ;
      RECT 0.168 10.104 42.168 10.152 ;
      RECT 0.168 10.488 42.168 10.536 ;
      RECT 0.168 10.872 42.168 10.920 ;
      RECT 0.168 11.256 42.168 11.304 ;
      RECT 0.168 11.640 42.168 11.688 ;
      RECT 0.168 12.024 42.168 12.072 ;
      RECT 0.168 12.408 42.168 12.456 ;
      RECT 0.168 12.792 42.168 12.840 ;
      RECT 0.168 13.176 42.168 13.224 ;
      RECT 0.168 13.560 42.168 13.608 ;
      RECT 0.168 13.944 42.168 13.992 ;
      RECT 0.168 14.328 42.168 14.376 ;
      RECT 0.168 14.712 42.168 14.760 ;
      RECT 0.168 15.096 42.168 15.144 ;
      RECT 0.168 15.480 42.168 15.528 ;
      RECT 0.168 15.864 42.168 15.912 ;
      RECT 0.168 16.248 42.168 16.296 ;
      RECT 0.168 16.632 42.168 16.680 ;
      RECT 0.168 17.016 42.168 17.064 ;
      RECT 0.168 17.400 42.168 17.448 ;
      RECT 0.168 17.784 42.168 17.832 ;
      RECT 0.168 18.168 42.168 18.216 ;
      RECT 0.168 18.552 42.168 18.600 ;
      RECT 0.168 18.936 42.168 18.984 ;
      RECT 0.168 19.320 42.168 19.368 ;
      RECT 0.168 19.704 42.168 19.752 ;
      RECT 0.168 20.088 42.168 20.136 ;
      RECT 0.168 20.472 42.168 20.520 ;
      RECT 0.168 20.856 42.168 20.904 ;
      RECT 0.168 21.240 42.168 21.288 ;
      RECT 0.168 21.624 42.168 21.672 ;
      RECT 0.168 22.008 42.168 22.056 ;
    END
  END VSS
  PIN VDD
    DIRECTION INOUT ;
    USE POWER ;
    PORT
      LAYER M4 ;
      RECT 0.168 0.120 42.168 0.168 ;
      RECT 0.168 0.504 42.168 0.552 ;
      RECT 0.168 0.888 42.168 0.936 ;
      RECT 0.168 1.272 42.168 1.320 ;
      RECT 0.168 1.656 42.168 1.704 ;
      RECT 0.168 2.040 42.168 2.088 ;
      RECT 0.168 2.424 42.168 2.472 ;
      RECT 0.168 2.808 42.168 2.856 ;
      RECT 0.168 3.192 42.168 3.240 ;
      RECT 0.168 3.576 42.168 3.624 ;
      RECT 0.168 3.960 42.168 4.008 ;
      RECT 0.168 4.344 42.168 4.392 ;
      RECT 0.168 4.728 42.168 4.776 ;
      RECT 0.168 5.112 42.168 5.160 ;
      RECT 0.168 5.496 42.168 5.544 ;
      RECT 0.168 5.880 42.168 5.928 ;
      RECT 0.168 6.264 42.168 6.312 ;
      RECT 0.168 6.648 42.168 6.696 ;
      RECT 0.168 7.032 42.168 7.080 ;
      RECT 0.168 7.416 42.168 7.464 ;
      RECT 0.168 7.800 42.168 7.848 ;
      RECT 0.168 8.184 42.168 8.232 ;
      RECT 0.168 8.568 42.168 8.616 ;
      RECT 0.168 8.952 42.168 9.000 ;
      RECT 0.168 9.336 42.168 9.384 ;
      RECT 0.168 9.720 42.168 9.768 ;
      RECT 0.168 10.104 42.168 10.152 ;
      RECT 0.168 10.488 42.168 10.536 ;
      RECT 0.168 10.872 42.168 10.920 ;
      RECT 0.168 11.256 42.168 11.304 ;
      RECT 0.168 11.640 42.168 11.688 ;
      RECT 0.168 12.024 42.168 12.072 ;
      RECT 0.168 12.408 42.168 12.456 ;
      RECT 0.168 12.792 42.168 12.840 ;
      RECT 0.168 13.176 42.168 13.224 ;
      RECT 0.168 13.560 42.168 13.608 ;
      RECT 0.168 13.944 42.168 13.992 ;
      RECT 0.168 14.328 42.168 14.376 ;
      RECT 0.168 14.712 42.168 14.760 ;
      RECT 0.168 15.096 42.168 15.144 ;
      RECT 0.168 15.480 42.168 15.528 ;
      RECT 0.168 15.864 42.168 15.912 ;
      RECT 0.168 16.248 42.168 16.296 ;
      RECT 0.168 16.632 42.168 16.680 ;
      RECT 0.168 17.016 42.168 17.064 ;
      RECT 0.168 17.400 42.168 17.448 ;
      RECT 0.168 17.784 42.168 17.832 ;
      RECT 0.168 18.168 42.168 18.216 ;
      RECT 0.168 18.552 42.168 18.600 ;
      RECT 0.168 18.936 42.168 18.984 ;
      RECT 0.168 19.320 42.168 19.368 ;
      RECT 0.168 19.704 42.168 19.752 ;
      RECT 0.168 20.088 42.168 20.136 ;
      RECT 0.168 20.472 42.168 20.520 ;
      RECT 0.168 20.856 42.168 20.904 ;
      RECT 0.168 21.240 42.168 21.288 ;
      RECT 0.168 21.624 42.168 21.672 ;
      RECT 0.168 22.008 42.168 22.056 ;
    END
  END VDD
  OBS
    LAYER M1 ;
    RECT 0 0 42.336 22.320 ;
    LAYER M2 ;
    RECT 0 0 42.336 22.320 ;
    LAYER M3 ;
    RECT 0 0 42.336 22.320 ;
    LAYER M4 ;
    RECT 0 0 42.336 22.320 ;
  END
END fakeram_65x160_1r1w

END LIBRARY
